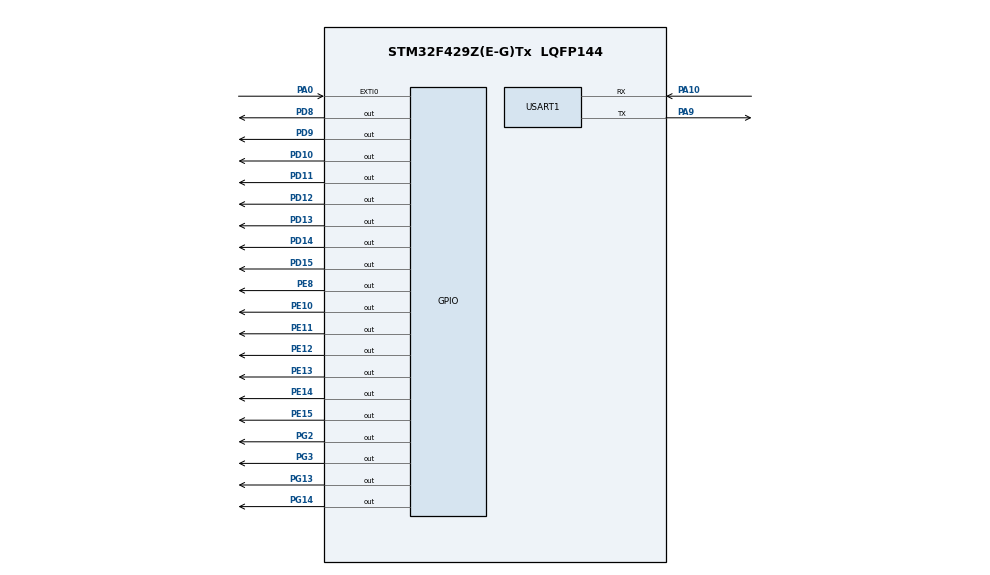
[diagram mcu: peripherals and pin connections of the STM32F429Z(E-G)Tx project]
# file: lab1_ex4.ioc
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Mcu.Family=STM32F4
Mcu.Name=STM32F429Z(E-G)Tx
Mcu.Package=LQFP144
NVIC.EXTI0_IRQn=true\:0\:0\:false\:false\:true\:true\:true\:true
NVIC.PriorityGroup=NVIC_PRIORITYGROUP_4
NVIC.TIM6_DAC_IRQn=true\:0\:0\:false\:false\:true\:true\:true\:true
PA0/WKUP.Signal=GPXTI0
PA10.Mode=Asynchronous
PA10.Signal=USART1_RX
PA9.Mode=Asynchronous
PA9.Signal=USART1_TX
PD10.Signal=GPIO_Output
PD11.Signal=GPIO_Output
PD12.Signal=GPIO_Output
PD13.Signal=GPIO_Output
PD14.Signal=GPIO_Output
PD15.Signal=GPIO_Output
PD8.Signal=GPIO_Output
PD9.Signal=GPIO_Output
PE10.Signal=GPIO_Output
PE11.Signal=GPIO_Output
PE12.Signal=GPIO_Output
PE13.Signal=GPIO_Output
PE14.Signal=GPIO_Output
PE15.Signal=GPIO_Output
PE8.Signal=GPIO_Output
PE9.Signal=EVENTOUT
PG13.Signal=GPIO_Output
PG14.Signal=GPIO_Output
PG2.Signal=GPIO_Output
PG3.Signal=GPIO_Output
PH0/OSC_IN.Mode=HSE-External-Oscillator
PH0/OSC_IN.Signal=RCC_OSC_IN
PH1/OSC_OUT.Mode=HSE-External-Oscillator
PH1/OSC_OUT.Signal=RCC_OSC_OUT
ProjectManager.HeapSize=0x200
ProjectManager.StackSize=0x400
ProjectManager.TargetToolchain=STM32CubeIDE
RCC.AHBFreq_Value=16000000
RCC.APB1Freq_Value=16000000
RCC.APB2Freq_Value=16000000
RCC.CortexFreq_Value=16000000
RCC.HSE_VALUE=25000000
RCC.HSI_VALUE=16000000
RCC.LSE_VALUE=32768
RCC.SYSCLKFreq_VALUE=16000000
RCC.VCOOutputFreq_Value=192000000
TIM6.Prescaler=89
USART1.VirtualMode=VM_ASYNC
VP_TIM6_VS_ClockSourceINT.Mode=Enable_Timer
board=custom

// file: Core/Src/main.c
/* USER CODE BEGIN Header */
/**
  ******************************************************************************
  * @file           : main.c
  * @brief          : Main program body
  ******************************************************************************
  * @attention
  *
  * Copyright (c) 2026 STMicroelectronics.
  * All rights reserved.
  *
  * This software is licensed under terms that can be found in the LICENSE file
  * in the root directory of this software component.
  * If no LICENSE file comes with this software, it is provided AS-IS.
  *
  ******************************************************************************
  */
/* USER CODE END Header */
#include "main.h"

/* USER CODE BEGIN Includes */
#include "7seg.h"
#include "irda.h"
#include "stdio.h"
#include "string.h"
/* USER CODE END Includes */

TIM_HandleTypeDef htim6;

UART_HandleTypeDef huart1;

/* USER CODE BEGIN PV */
int tim6_count;
uint8_t LED_Value = 0x00;
int effect_mode = 0;
int step_count = 0;
int spot_dir = 0;
int spot_index = 0;
int led4_state = 0;
uint32_t last_led_time = 0;
/* USER CODE END PV */

void SystemClock_Config(void);
static void MX_GPIO_Init(void);
static void MX_TIM6_Init(void);
static void MX_USART1_UART_Init(void);

/* USER CODE BEGIN 0 */
extern int command_ok;
extern unsigned char irda_cmd[4];

void DisplayLEDs(int mode)
{
    if (mode == 1)      // Running spot L
    {
        LED_Value = (0x01 << step_count);
        step_count++;
        if (step_count >= 8) step_count = 0;
    }
    else if (mode == 2) // Running spot R
    {
        LED_Value = (0x80 >> step_count);
        step_count++;
        if (step_count >= 8) step_count = 0;
    }
    else if (mode == 3) // Flash
    {
        LED_Value = ~LED_Value;
    }
    else if (mode == 4) // Spot Bumber
    {
        if (spot_dir == 0) {
            LED_Value = (0x80 >> spot_index) | (0x01 << spot_index);
            spot_index++;
            if (spot_index >= 4) { spot_dir = 1; spot_index = 3; }
        } else {
            spot_index--;
            LED_Value = (0x80 >> spot_index) | (0x01 << spot_index);
            if (spot_index <= 0) { spot_dir = 0; spot_index = 0; }
        }
    }

    HAL_GPIO_WritePin(GPIOD, GPIO_PIN_15, (LED_Value & 0x80) ? GPIO_PIN_SET : GPIO_PIN_RESET);
    HAL_GPIO_WritePin(GPIOD, GPIO_PIN_14, (LED_Value & 0x40) ? GPIO_PIN_SET : GPIO_PIN_RESET);
    HAL_GPIO_WritePin(GPIOD, GPIO_PIN_13, (LED_Value & 0x20) ? GPIO_PIN_SET : GPIO_PIN_RESET);
    HAL_GPIO_WritePin(GPIOD, GPIO_PIN_12, (LED_Value & 0x10) ? GPIO_PIN_SET : GPIO_PIN_RESET);
    HAL_GPIO_WritePin(GPIOD, GPIO_PIN_11, (LED_Value & 0x08) ? GPIO_PIN_SET : GPIO_PIN_RESET);
    HAL_GPIO_WritePin(GPIOD, GPIO_PIN_10, (LED_Value & 0x04) ? GPIO_PIN_SET : GPIO_PIN_RESET);
    HAL_GPIO_WritePin(GPIOD, GPIO_PIN_9,  (LED_Value & 0x02) ? GPIO_PIN_SET : GPIO_PIN_RESET);
    HAL_GPIO_WritePin(GPIOD, GPIO_PIN_8,  (LED_Value & 0x01) ? GPIO_PIN_SET : GPIO_PIN_RESET);
}

void ProcessIrCommand(uint8_t cmd)
{
    Set7SegDisplayValue(cmd);

    if (cmd == 0x1C)        // OK
    {
        led4_state = !led4_state;
        HAL_GPIO_WritePin(GPIOG, GPIO_PIN_14,
            led4_state ? GPIO_PIN_SET : GPIO_PIN_RESET);
    }
    else if (cmd == 0x45)   // 1 -> Running spot L
    {
        effect_mode = 1;
        step_count = 0;
    }
    else if (cmd == 0x46)   // 2 -> Running spot R
    {
        effect_mode = 2;
        step_count = 0;
    }
    else if (cmd == 0x47)   // 3 -> Flash
    {
        effect_mode = 3;
        LED_Value = 0xFF;
    }
    else if (cmd == 0x44)   // 4 -> Spot Bumber
    {
        effect_mode = 4;
        spot_index = 0;
        spot_dir = 0;
    }
}
/* USER CODE END 0 */

int main(void)
{

  /* MCU Configuration--------------------------------------------------------*/

  /* Reset of all peripherals, Initializes the Flash interface and the Systick. */
  HAL_Init();

  /* Configure the system clock */
  SystemClock_Config();

  /* Initialize all configured peripherals */
  MX_GPIO_Init();
  MX_TIM6_Init();
  MX_USART1_UART_Init();
  /* USER CODE BEGIN 2 */
  HAL_TIM_Base_Start_IT(&htim6);
  command_ok = 0;
  tim6_count = 0;
  Set7SegDisplayValue(0);
  /* USER CODE END 2 */

  /* Infinite loop */
  /* USER CODE BEGIN WHILE */
  while (1)
  {
		Run7SegDisplay();

		if (HAL_GetTick() - last_led_time >= 200 && effect_mode > 0)
		{
		    last_led_time = HAL_GetTick();
		    DisplayLEDs(effect_mode);
		}

		if (command_ok)
		{
			IrDecode();
			ProcessIrCommand(irda_cmd[2]);
			command_ok = 0;
		}

		HAL_Delay(5);
    /* USER CODE END WHILE */

  }
}

void SystemClock_Config(void)
{
  RCC_OscInitTypeDef RCC_OscInitStruct = {0};
  RCC_ClkInitTypeDef RCC_ClkInitStruct = {0};

  /** Configure the main internal regulator output voltage
  */
  __HAL_RCC_PWR_CLK_ENABLE();
  __HAL_PWR_VOLTAGESCALING_CONFIG(PWR_REGULATOR_VOLTAGE_SCALE1);

  /** Initializes the RCC Oscillators according to the specified parameters
  * in the RCC_OscInitTypeDef structure.
  */
  RCC_OscInitStruct.OscillatorType = RCC_OSCILLATORTYPE_HSE;
  RCC_OscInitStruct.HSEState = RCC_HSE_ON;
  RCC_OscInitStruct.PLL.PLLState = RCC_PLL_ON;
  RCC_OscInitStruct.PLL.PLLSource = RCC_PLLSOURCE_HSE;
  RCC_OscInitStruct.PLL.PLLM = 4;
  RCC_OscInitStruct.PLL.PLLN = 180;
  RCC_OscInitStruct.PLL.PLLP = RCC_PLLP_DIV2;
  RCC_OscInitStruct.PLL.PLLQ = 4;
  if (HAL_RCC_OscConfig(&RCC_OscInitStruct) != HAL_OK)
  {
    Error_Handler();
  }

  /** Activate the Over-Drive mode
  */
  if (HAL_PWREx_EnableOverDrive() != HAL_OK)
  {
    Error_Handler();
  }

  /** Initializes the CPU, AHB and APB buses clocks
  */
  RCC_ClkInitStruct.ClockType = RCC_CLOCKTYPE_HCLK|RCC_CLOCKTYPE_SYSCLK
                              |RCC_CLOCKTYPE_PCLK1|RCC_CLOCKTYPE_PCLK2;
  RCC_ClkInitStruct.SYSCLKSource = RCC_SYSCLKSOURCE_PLLCLK;
  RCC_ClkInitStruct.AHBCLKDivider = RCC_SYSCLK_DIV1;
  RCC_ClkInitStruct.APB1CLKDivider = RCC_HCLK_DIV4;
  RCC_ClkInitStruct.APB2CLKDivider = RCC_HCLK_DIV2;

  if (HAL_RCC_ClockConfig(&RCC_ClkInitStruct, FLASH_LATENCY_5) != HAL_OK)
  {
    Error_Handler();
  }
}

static void MX_TIM6_Init(void)
{

  TIM_MasterConfigTypeDef sMasterConfig = {0};

  htim6.Instance = TIM6;
  htim6.Init.Prescaler = 89;
  htim6.Init.CounterMode = TIM_COUNTERMODE_UP;
  htim6.Init.Period = 99;
  htim6.Init.AutoReloadPreload = TIM_AUTORELOAD_PRELOAD_DISABLE;
  if (HAL_TIM_Base_Init(&htim6) != HAL_OK)
  {
    Error_Handler();
  }
  sMasterConfig.MasterOutputTrigger = TIM_TRGO_RESET;
  sMasterConfig.MasterSlaveMode = TIM_MASTERSLAVEMODE_DISABLE;
  if (HAL_TIMEx_MasterConfigSynchronization(&htim6, &sMasterConfig) != HAL_OK)
  {
    Error_Handler();
  }

}

static void MX_USART1_UART_Init(void)
{

  huart1.Instance = USART1;
  huart1.Init.BaudRate = 115200;
  huart1.Init.WordLength = UART_WORDLENGTH_8B;
  huart1.Init.StopBits = UART_STOPBITS_1;
  huart1.Init.Parity = UART_PARITY_NONE;
  huart1.Init.Mode = UART_MODE_TX_RX;
  huart1.Init.HwFlowCtl = UART_HWCONTROL_NONE;
  huart1.Init.OverSampling = UART_OVERSAMPLING_16;
  if (HAL_UART_Init(&huart1) != HAL_OK)
  {
    Error_Handler();
  }

}

static void MX_GPIO_Init(void)
{
  GPIO_InitTypeDef GPIO_InitStruct = {0};

  /* GPIO Ports Clock Enable */
  __HAL_RCC_GPIOH_CLK_ENABLE();
  __HAL_RCC_GPIOA_CLK_ENABLE();
  __HAL_RCC_GPIOE_CLK_ENABLE();
  __HAL_RCC_GPIOD_CLK_ENABLE();
  __HAL_RCC_GPIOG_CLK_ENABLE();

  /*Configure GPIO pin Output Level */
  HAL_GPIO_WritePin(GPIOE, GPIO_PIN_8|GPIO_PIN_10|GPIO_PIN_11|GPIO_PIN_12
                          |GPIO_PIN_13|GPIO_PIN_14|GPIO_PIN_15, GPIO_PIN_RESET);

  /*Configure GPIO pin Output Level */
  HAL_GPIO_WritePin(GPIOD, GPIO_PIN_8|GPIO_PIN_9|GPIO_PIN_10|GPIO_PIN_11
                          |GPIO_PIN_12|GPIO_PIN_13|GPIO_PIN_14|GPIO_PIN_15, GPIO_PIN_RESET);

  /*Configure GPIO pin Output Level */
  HAL_GPIO_WritePin(GPIOG, GPIO_PIN_2|GPIO_PIN_3|GPIO_PIN_13|GPIO_PIN_14, GPIO_PIN_RESET);

  /*Configure GPIO pin : PA0 */
  GPIO_InitStruct.Pin = GPIO_PIN_0;
  GPIO_InitStruct.Mode = GPIO_MODE_IT_RISING;
  GPIO_InitStruct.Pull = GPIO_NOPULL;
  HAL_GPIO_Init(GPIOA, &GPIO_InitStruct);

  /*Configure GPIO pins : PE8 PE9 PE10 PE11
                           PE12 PE13 PE14 PE15 */
  GPIO_InitStruct.Pin = GPIO_PIN_8|GPIO_PIN_9|GPIO_PIN_10|GPIO_PIN_11
                          |GPIO_PIN_12|GPIO_PIN_13|GPIO_PIN_14|GPIO_PIN_15;
  GPIO_InitStruct.Mode = GPIO_MODE_OUTPUT_PP;
  GPIO_InitStruct.Pull = GPIO_NOPULL;
  GPIO_InitStruct.Speed = GPIO_SPEED_FREQ_LOW;
  HAL_GPIO_Init(GPIOE, &GPIO_InitStruct);

  /*Configure GPIO pins : PD8 PD9 PD10 PD11
                           PD12 PD13 PD14 PD15 */
  GPIO_InitStruct.Pin = GPIO_PIN_8|GPIO_PIN_9|GPIO_PIN_10|GPIO_PIN_11
                          |GPIO_PIN_12|GPIO_PIN_13|GPIO_PIN_14|GPIO_PIN_15;
  GPIO_InitStruct.Mode = GPIO_MODE_OUTPUT_PP;
  GPIO_InitStruct.Pull = GPIO_NOPULL;
  GPIO_InitStruct.Speed = GPIO_SPEED_FREQ_LOW;
  HAL_GPIO_Init(GPIOD, &GPIO_InitStruct);

  /*Configure GPIO pins : PG2 PG3 PG13 PG14 */
  GPIO_InitStruct.Pin = GPIO_PIN_2|GPIO_PIN_3|GPIO_PIN_13|GPIO_PIN_14;
  GPIO_InitStruct.Mode = GPIO_MODE_OUTPUT_PP;
  GPIO_InitStruct.Pull = GPIO_NOPULL;
  GPIO_InitStruct.Speed = GPIO_SPEED_FREQ_LOW;
  HAL_GPIO_Init(GPIOG, &GPIO_InitStruct);

  /*Configure GPIO pin : PG5 */
  GPIO_InitStruct.Pin = GPIO_PIN_5;
  GPIO_InitStruct.Mode = GPIO_MODE_IT_FALLING;
  GPIO_InitStruct.Pull = GPIO_PULLUP;
  HAL_GPIO_Init(GPIOG, &GPIO_InitStruct);

  /* EXTI interrupt init*/
  HAL_NVIC_SetPriority(EXTI9_5_IRQn, 0, 0);
  HAL_NVIC_EnableIRQ(EXTI9_5_IRQn);

  HAL_NVIC_SetPriority(TIM6_DAC_IRQn, 1, 0);
  HAL_NVIC_EnableIRQ(TIM6_DAC_IRQn);

}

void Error_Handler(void)
{
  __disable_irq();
  while (1)
  {
  }
}
